VERSION 5.8 ;
BUSBITCHARS "[]" ;
DIVIDERCHAR "/" ;
UNITS
    DATABASE MICRONS 1000 ;
END UNITS

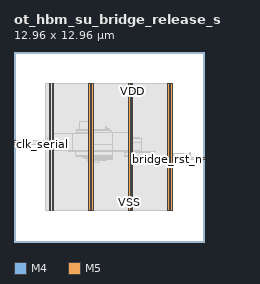
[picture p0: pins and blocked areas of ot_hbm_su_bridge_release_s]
MACRO ot_hbm_su_bridge_release_s
  FOREIGN ot_hbm_su_bridge_release_s 0 0 ;
  CLASS BLOCK ;
  SIZE 12.96 BY 12.96 ;
  PIN bridge_rst_n
    DIRECTION OUTPUT ;
    USE SIGNAL ;
    PORT
      LAYER M4 ;
        RECT  12.876 5.616 12.96 5.64 ;
    END
  END bridge_rst_n
  PIN clk_serial
    DIRECTION INPUT ;
    USE SIGNAL ;
    PORT
      LAYER M4 ;
        RECT  0 6.624 0.084 6.648 ;
    END
  END clk_serial
  PIN fault
    DIRECTION OUTPUT ;
    USE SIGNAL ;
    PORT
      LAYER M4 ;
        RECT  12.876 5.76 12.96 5.784 ;
    END
  END fault
  PIN prog_busy
    DIRECTION INPUT ;
    USE SIGNAL ;
    PORT
      LAYER M4 ;
        RECT  0 6.768 0.084 6.792 ;
    END
  END prog_busy
  PIN rst_n
    DIRECTION INPUT ;
    USE SIGNAL ;
    PORT
      LAYER M4 ;
        RECT  0 6.912 0.084 6.936 ;
    END
  END rst_n
  PIN VDD
    DIRECTION INOUT ;
    USE POWER ;
    PORT
      LAYER M5 ;
        RECT  10.692 2.151 10.812 10.809 ;
        RECT  7.992 2.151 8.112 10.809 ;
        RECT  5.292 2.151 5.412 10.809 ;
        RECT  2.592 2.151 2.712 10.809 ;
    END
  END VDD
  PIN VSS
    DIRECTION INOUT ;
    USE GROUND ;
    PORT
      LAYER M5 ;
        RECT  10.5 2.137 10.62 10.823 ;
        RECT  7.8 2.137 7.92 10.823 ;
        RECT  5.1 2.137 5.22 10.823 ;
        RECT  2.4 2.137 2.52 10.823 ;
    END
  END VSS
  OBS
    LAYER RVTN ;
     RECT  2.16 2.16 10.8 2.295 ;
     RECT  2.16 2.565 10.8 2.835 ;
     RECT  2.16 3.105 10.8 3.375 ;
     RECT  2.16 3.645 10.8 3.915 ;
     RECT  2.16 4.185 10.8 4.455 ;
     RECT  2.16 4.725 10.8 4.995 ;
     RECT  2.16 5.265 10.8 5.535 ;
     RECT  2.16 5.805 10.8 6.075 ;
     RECT  2.16 6.345 10.8 6.615 ;
     RECT  2.16 6.885 10.8 7.155 ;
     RECT  2.16 7.425 10.8 7.695 ;
     RECT  2.16 7.965 10.8 8.235 ;
     RECT  2.16 8.505 10.8 8.775 ;
     RECT  2.16 9.045 10.8 9.315 ;
     RECT  2.16 9.585 10.8 9.855 ;
     RECT  2.16 10.125 10.8 10.395 ;
     RECT  2.16 10.665 10.8 10.8 ;
    LAYER RVTP ;
     RECT  2.16 2.295 10.8 2.565 ;
     RECT  2.16 2.835 10.8 3.105 ;
     RECT  2.16 3.375 10.8 3.645 ;
     RECT  2.16 3.915 10.8 4.185 ;
     RECT  2.16 4.455 10.8 4.725 ;
     RECT  2.16 4.995 10.8 5.265 ;
     RECT  2.16 5.535 10.8 5.805 ;
     RECT  2.16 6.075 10.8 6.345 ;
     RECT  2.16 6.615 10.8 6.885 ;
     RECT  2.16 7.155 10.8 7.425 ;
     RECT  2.16 7.695 10.8 7.965 ;
     RECT  2.16 8.235 10.8 8.505 ;
     RECT  2.16 8.775 10.8 9.045 ;
     RECT  2.16 9.315 10.8 9.585 ;
     RECT  2.16 9.855 10.8 10.125 ;
     RECT  2.16 10.395 10.8 10.665 ;
    LAYER M1 ;
     RECT  2.16 2.151 10.8 10.809 ;
    LAYER M2 ;
     RECT  2.16 2.151 10.8 10.809 ;
     RECT  10.8 2.421 10.812 10.539 ;
     RECT  10.812 5.706 10.895 6.066 ;
     RECT  10.895 6.048 12.011 6.066 ;
    LAYER M3 ;
     RECT  2.415 2.143 2.505 2.413 ;
     RECT  5.115 2.143 5.205 2.413 ;
     RECT  7.815 2.143 7.905 2.413 ;
     RECT  10.515 2.143 10.605 2.413 ;
     RECT  5.115 2.413 5.397 5.431 ;
     RECT  5.115 5.431 5.778 5.539 ;
     RECT  5.115 5.539 6.246 5.575 ;
     RECT  5.04 5.575 6.282 5.611 ;
     RECT  10.515 2.413 10.797 5.611 ;
     RECT  5.04 5.611 6.714 5.701 ;
     RECT  10.515 5.611 10.89 5.729 ;
     RECT  4.824 5.701 6.714 5.737 ;
     RECT  4.752 5.737 6.714 5.773 ;
     RECT  7.815 2.413 8.097 5.809 ;
     RECT  4.68 5.773 6.714 5.845 ;
     RECT  7.632 5.809 8.097 5.845 ;
     RECT  10.515 5.729 10.797 5.845 ;
     RECT  4.284 5.845 6.714 5.881 ;
     RECT  7.524 5.845 8.097 5.881 ;
     RECT  9.036 5.845 9.054 5.881 ;
     RECT  10.404 5.845 10.797 5.999 ;
     RECT  11.988 5.755 12.006 6.071 ;
     RECT  7.524 5.881 9.054 6.115 ;
     RECT  7.524 6.115 9.594 6.143 ;
     RECT  4.176 5.881 6.714 6.151 ;
     RECT  7.524 6.143 8.694 6.151 ;
     RECT  3.708 6.151 8.694 6.235 ;
     RECT  9.576 6.143 9.594 6.269 ;
     RECT  2.415 2.413 2.697 6.763 ;
     RECT  3.564 6.235 8.694 6.809 ;
     RECT  2.304 6.763 2.697 6.817 ;
     RECT  3.564 6.809 7.074 6.817 ;
     RECT  7.815 6.809 8.694 7.079 ;
     RECT  2.304 6.817 7.074 7.115 ;
     RECT  7.815 7.079 8.586 7.115 ;
     RECT  2.415 7.115 7.074 7.187 ;
     RECT  3.96 7.187 7.074 7.223 ;
     RECT  2.415 7.187 3.186 7.421 ;
     RECT  4.284 7.223 7.074 7.469 ;
     RECT  4.284 7.469 6.678 7.619 ;
     RECT  4.284 7.619 6.498 7.691 ;
     RECT  6.264 7.691 6.498 7.763 ;
     RECT  6.264 7.763 6.282 7.889 ;
     RECT  4.464 7.691 5.397 8.195 ;
     RECT  2.415 7.421 2.697 10.547 ;
     RECT  5.115 8.195 5.397 10.547 ;
     RECT  7.815 7.115 8.097 10.547 ;
     RECT  10.515 5.999 10.797 10.547 ;
     RECT  2.415 10.547 2.505 10.817 ;
     RECT  5.115 10.547 5.205 10.817 ;
     RECT  7.815 10.547 7.905 10.817 ;
     RECT  10.515 10.547 10.605 10.817 ;
    LAYER M4 ;
     RECT  0.06 6.624 2.408 6.936 ;
     RECT  2.408 2.148 2.512 10.812 ;
     RECT  2.512 2.418 2.704 10.542 ;
     RECT  2.704 6.24 5.108 7.416 ;
     RECT  5.108 2.148 5.212 10.812 ;
     RECT  5.212 2.418 5.404 10.542 ;
     RECT  5.404 6.624 6.685 7.464 ;
     RECT  6.685 6.24 7.808 7.464 ;
     RECT  7.808 2.148 7.912 10.812 ;
     RECT  7.912 2.418 8.104 10.542 ;
     RECT  10.508 2.148 10.612 10.812 ;
     RECT  10.612 2.418 10.804 10.542 ;
     RECT  10.804 5.616 11.977 5.64 ;
     RECT  11.977 5.616 12.924 5.784 ;
    LAYER M5 ;
     RECT  2.4 2.137 2.52 2.151 ;
     RECT  5.1 2.137 5.22 2.151 ;
     RECT  7.8 2.137 7.92 2.151 ;
     RECT  10.5 2.137 10.62 2.151 ;
     RECT  3.984 6.229 4.008 7.427 ;
     RECT  2.4 2.151 2.712 10.809 ;
     RECT  5.1 2.151 5.412 10.809 ;
     RECT  7.8 2.151 8.112 10.809 ;
     RECT  10.5 2.151 10.812 10.809 ;
     RECT  2.4 10.809 2.52 10.823 ;
     RECT  5.1 10.809 5.22 10.823 ;
     RECT  7.8 10.809 7.92 10.823 ;
     RECT  10.5 10.809 10.62 10.823 ;
  END
END ot_hbm_su_bridge_release_s
END LIBRARY
